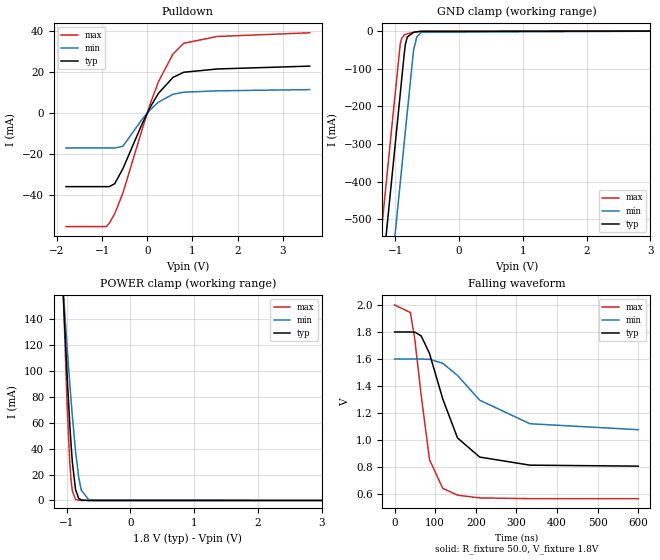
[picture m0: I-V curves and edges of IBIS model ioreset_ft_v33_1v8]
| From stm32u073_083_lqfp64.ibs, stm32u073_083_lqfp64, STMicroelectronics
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[Model]   ioreset_ft_v33_1v8
Model_type I/O_open_drain
Polarity   Inverting
Enable   Active-Low
| CAP_THRESHOLD on pad IOFT is "UDTCAPC" :
| Rising=30.0% of vddiom   Falling=70.0% of vddiom
| C_comp min and max val. don't necessarily correlate with the min and max pvt
| but are the smallest and greatest pad capacitance found.
| var   typ   min   max
C_comp   1.77220pF  1.75625pF  1.80435pF
|C_comp_pulldown   1.77220pF  1.75625pF  1.80435pF
Vinl = 800.0mV
Vinh = 1.0V
Vmeas = 900.0mV   | Reference voltage for timing measurements
Cref  = 50.0pF   | Timing specification test load capacitance value
Rref  = 1.0MOhm   | Timing specification test load resistance value
Vref  = 990.0mV   | Timing specification test load voltage
[Model Spec]
| TIME_THRESHOLD on pin ZIV33M is "CMOS" :
| Rising=50.0% of vddiom   Falling=50.0% of vddiom
Vinl 728.70000mV 652.70000mV 817.70000mV
Vinh 1.06430V 953.30000mV 1.16330V
| variable   typ   min   max
[Temperature Range] 25.0 125.0 -40.0
| variable   typ   min   max
[Voltage Range] 1.8V 1.6V 2.0V
| variable   typ   min   max
[POWER Clamp Reference] 1.8V 1.6V 2.0V
| variable   typ   min   max
[GND Clamp Reference] 0V 0V 0V
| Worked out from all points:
|   slope of the pulldown table from 0 to 0.27 V, typ, clamps not added: 26.5 ohm
|   GND clamp passes 1 mA (typ) near -0.61 V on its own axis
|   POWER clamp passes 1 mA (typ) near -0.80 V on its own axis
|   falling waveform, R_fixture 50.0, V_fixture 1.8V: 20-80 % time 66.8ns typ, 115ns min, 35ns max; typ from 1.8 V to 0.809 V
[POWER Clamp]
-1.8V     1.076A     768.4mA    1.428A
-1.06V    166.8mA    167.3mA    172.4mA
-1.05V    156mA      159.9mA    156.7mA
-990mV    94.58mA    117mA      71.25mA
-950mV    58.69mA    90.08mA    29.27mA
-930mV    43.17mA    77.31mA    15.67mA
-910mV    29.83mA    65.11mA    7.377mA
-860mV    8.434mA    38.02mA    795.5uA
-810mV    1.577mA    17.82mA    74.4uA
-770mV    365.4uA    7.942mA    11.04uA
-650mV    4.138uA    347.7uA    35.91nA
3.6V      0A         0A         0A
[GND Clamp]
-1.8V     -1.663A    -1.899A    -1.527A
-1.24V    -711.1mA   -947.1mA   -574.7mA
-1.05V    -388.1mA   -624.1mA   -251.7mA
-920mV    -167.1mA   -403.1mA   -34.95mA
-900mV    -133.1mA   -369.1mA   -20.48mA
-860mV    -65.11mA   -301.1mA   -10.77mA
-840mV    -35.78mA   -267.1mA   -9.029mA
-810mV    -15.99mA   -216.1mA   -7.371mA
-710mV    -3.278mA   -49.25mA   -3.599mA
-660mV    -1.937mA   -15.15mA   -2.17mA
-590mV    -787.4uA   -3.466mA   -783.3uA
3.6V      222.6pA    5.487nA    208.7pA
| variable   typ   min   max
[Pullup Reference] 1.8V 1.6V 2.0V
| variable   typ   min   max
[Pulldown Reference] 0V 0V 0V
[Pulldown]
-1.8V     -35.76mA   -16.97mA   -55.17mA
-910mV    -35.76mA   -16.97mA   -55.17mA
-840mV    -35.76mA   -16.97mA   -53.52mA
-720mV    -34.31mA   -16.97mA   -48.86mA
-540mV    -27.04mA   -16.13mA   -38.89mA
-120mV    -5.569mA   -3.236mA   -8.457mA
70mV      3.02mA     1.701mA    4.715mA
250mV     9.626mA    5.312mA    15.31mA
570mV     17.31mA    9.123mA    28.69mA
810mV     19.83mA    10.13mA    33.92mA
1.56V     21.42mA    10.8mA     37.22mA
3.6V      22.8mA     11.39mA    38.98mA
[Ramp]
dV/dt_r 594.84288mV/2.11314ns 314.69495mV/4.1874ns 857.44659mV/1.03315ns
dV/dt_f 594.80234mV/66.78338ns 313.27543mV/114.67012ns 859.13149mV/34.95699ns
R_load = 50.0
| Removed startup time: 0s 0s 0s  .
| Removed end time: 599.85ns.
[Falling Waveform]
R_fixture   = 50.0
V_fixture   = 1.8V
V_fixture_min = 1.6V
V_fixture_max = 2.0V
0s        1.8V       1.6V       2V
39ns      1.8V       1.6V       1.944V
49.9ns    1.799V     1.6V       1.745V
65.6ns    1.771V     1.6V       1.333V
86.1ns    1.641V     1.598V     856.1mV
118.7ns   1.305V     1.569V     644.7mV
155ns     1.017V     1.479V     594.1mV
209.6ns   875.6mV    1.296V     574.1mV
333.3ns   815.9mV    1.122V     568.4mV
599.9ns   808.7mV    1.078V     568.1mV
